VERSION 5.7 ;
BUSBITCHARS "[]" ; 
DIVIDERCHAR "/" ;

UNITS
    DATABASE MICRONS 2000 ;
END UNITS

MANUFACTURINGGRID 0.005 ;

SITE CoreSite
    SIZE 0.210 BY 1.050 ;
    CLASS CORE ;
    SYMMETRY Y ;
END CoreSite

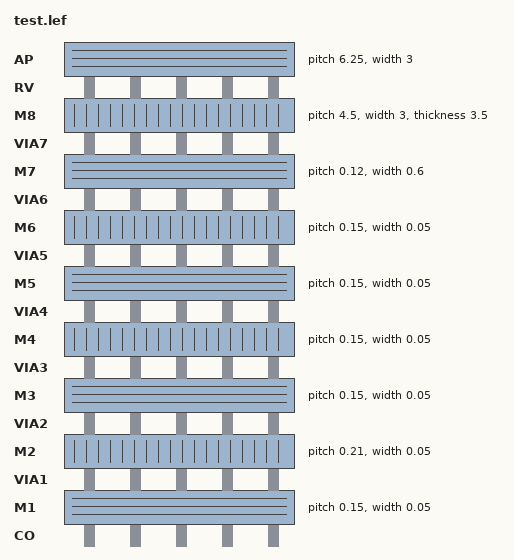
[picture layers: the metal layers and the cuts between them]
LAYER CO
    TYPE CUT ;
END CO

LAYER M1
    TYPE ROUTING ;
    DIRECTION HORIZONTAL ;
    PITCH 0.15 0.150 ;
    OFFSET 0.000 0.000 ;
    WIDTH 0.050000 ;
END M1

LAYER VIA1
    TYPE CUT ;
END VIA1

LAYER M2
    TYPE ROUTING ;
    DIRECTION VERTICAL ;
    PITCH 0.21 0.150 ;
    OFFSET 0.105 0.000 ;
    WIDTH 0.050000 ;
END M2

LAYER VIA2
    TYPE CUT ;
END VIA2

LAYER M3
    TYPE ROUTING ;
    DIRECTION HORIZONTAL ;
    PITCH 0.150 0.150 ;
    OFFSET 0.000 0.000 ;
    WIDTH 0.050000 ;
END M3

LAYER VIA3
    TYPE CUT ;
END VIA3

LAYER M4
    TYPE ROUTING ;
    DIRECTION VERTICAL ;
    PITCH 0.150 0.150 ;
    OFFSET 0.000 0.000 ;
    WIDTH 0.050000 ;
END M4

LAYER VIA4
    TYPE CUT ;
END VIA4

LAYER M5
    TYPE ROUTING ;
    DIRECTION HORIZONTAL ;
    PITCH 0.150 0.150 ;
    OFFSET 0.000 0.000 ;
    WIDTH 0.050000 ;
END M5

LAYER VIA5
    TYPE CUT ;
END VIA5

LAYER M6
    TYPE ROUTING ;
    DIRECTION VERTICAL ;
    PITCH 0.150 0.150 ;
    OFFSET 0.000 0.000 ;
    WIDTH 0.050000 ;
END M6

LAYER VIA6
    TYPE CUT ;
END VIA6

LAYER M7
    TYPE ROUTING ;
    DIRECTION HORIZONTAL ;
    PITCH 0.120000 0.120000 ;
    OFFSET 0.000000 0.000000 ;
    WIDTH 0.600000 ;
END M7

LAYER VIA7
    TYPE CUT ;
END VIA7

LAYER M8
    TYPE ROUTING ;
    DIRECTION VERTICAL ;
    PITCH 4.5 ;
    OFFSET 0 ;
    HEIGHT 1.825 ;
    THICKNESS 3.5 ;
    FILLACTIVESPACING 3 ;
    WIDTH 3.0 ;
END M8

LAYER RV
    TYPE CUT ;
END RV

LAYER AP
    TYPE ROUTING ;
    DIRECTION HORIZONTAL ;
    PITCH   6.250000 6.250000 ;
    OFFSET 0.000000 0.000000 ;
    WIDTH   3.000000 ;
    
END AP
